One B-rep face of a CAD part: STEP entity #52863.
In plain terms, the planar face has unit normal (0, 0, 1).
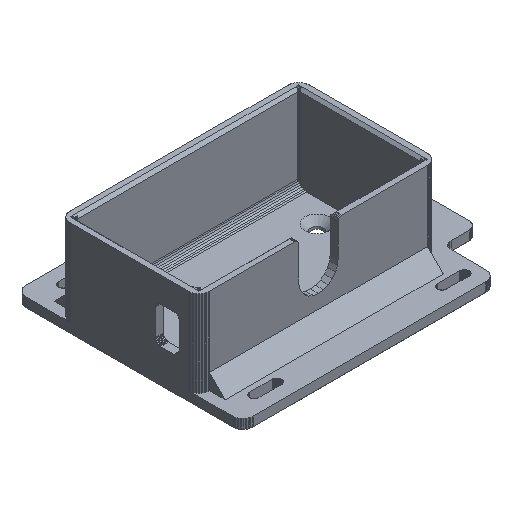
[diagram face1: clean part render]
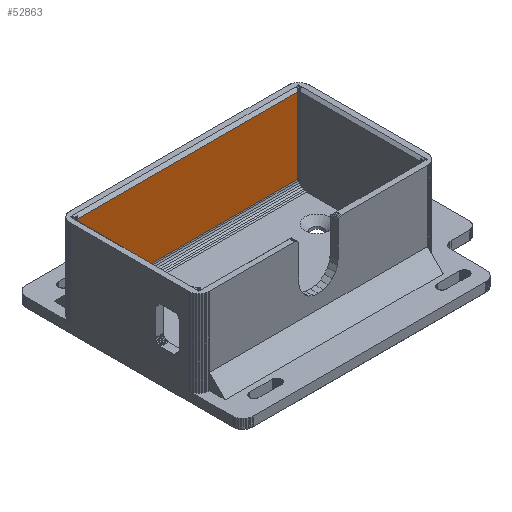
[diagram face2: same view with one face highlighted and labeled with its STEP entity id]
Its self-contained STEP definition (entity closure, numbers rounded to 3 decimals):
#43876 = PLANE('',#43877);
#43877 = AXIS2_PLACEMENT_3D('',#43878,#43879,#43880);
#43878 = CARTESIAN_POINT('',(37.5,160.35,-24.5));
#43879 = DIRECTION('',(0.,0.707,0.707)
  );
#43880 = DIRECTION('',(0.,-0.707,0.707
    ));
#49672 = VERTEX_POINT('',#49673);
#49673 = CARTESIAN_POINT('',(-47.9,159.35,-23.5));
#49699 = EDGE_CURVE('',#49700,#49672,#49702,.T.);
#49700 = VERTEX_POINT('',#49701);
#49701 = CARTESIAN_POINT('',(35.9,159.35,-23.5));
#49702 = SURFACE_CURVE('',#49703,(#49707,#49714),.PCURVE_S1.);
#49703 = LINE('',#49704,#49705);
#49704 = CARTESIAN_POINT('',(37.5,159.35,-23.5));
#49705 = VECTOR('',#49706,1.);
#49706 = DIRECTION('',(-1.,0.,0.));
#49707 = PCURVE('',#43876,#49708);
#49708 = DEFINITIONAL_REPRESENTATION('',(#49709),#49713);
#49709 = LINE('',#49710,#49711);
#49710 = CARTESIAN_POINT('',(1.414,0.));
#49711 = VECTOR('',#49712,1.);
#49712 = DIRECTION('',(0.,-1.));
#49713 = ( GEOMETRIC_REPRESENTATION_CONTEXT(2) 
PARAMETRIC_REPRESENTATION_CONTEXT() REPRESENTATION_CONTEXT('2D SPACE',''
  ) );
#49714 = PCURVE('',#49715,#49720);
#49715 = PLANE('',#49716);
#49716 = AXIS2_PLACEMENT_3D('',#49717,#49718,#49719);
#49717 = CARTESIAN_POINT('',(-47.9,160.35,-23.5));
#49718 = DIRECTION('',(0.,0.,1.));
#49719 = DIRECTION('',(1.,0.,0.));
#49720 = DEFINITIONAL_REPRESENTATION('',(#49721),#49725);
#49721 = LINE('',#49722,#49723);
#49722 = CARTESIAN_POINT('',(85.4,-1.));
#49723 = VECTOR('',#49724,1.);
#49724 = DIRECTION('',(-1.,0.));
#49725 = ( GEOMETRIC_REPRESENTATION_CONTEXT(2) 
PARAMETRIC_REPRESENTATION_CONTEXT() REPRESENTATION_CONTEXT('2D SPACE',''
  ) );
#52826 = PLANE('',#52827);
#52827 = AXIS2_PLACEMENT_3D('',#52828,#52829,#52830);
#52828 = CARTESIAN_POINT('',(35.9,160.35,-23.5));
#52829 = DIRECTION('',(-0.052,0.,
    0.999));
#52830 = DIRECTION('',(0.999,0.,
    0.052));
#52863 = ADVANCED_FACE('',(#52864),#49715,.T.);
#52864 = FACE_BOUND('',#52865,.T.);
#52865 = EDGE_LOOP('',(#52866,#52867,#52895,#52923));
#52866 = ORIENTED_EDGE('',*,*,#49699,.T.);
#52867 = ORIENTED_EDGE('',*,*,#52868,.T.);
#52868 = EDGE_CURVE('',#49672,#52869,#52871,.T.);
#52869 = VERTEX_POINT('',#52870);
#52870 = CARTESIAN_POINT('',(-47.9,130.55,-23.5));
#52871 = SURFACE_CURVE('',#52872,(#52876,#52883),.PCURVE_S1.);
#52872 = LINE('',#52873,#52874);
#52873 = CARTESIAN_POINT('',(-47.9,160.35,-23.5));
#52874 = VECTOR('',#52875,1.);
#52875 = DIRECTION('',(0.,-1.,0.));
#52876 = PCURVE('',#49715,#52877);
#52877 = DEFINITIONAL_REPRESENTATION('',(#52878),#52882);
#52878 = LINE('',#52879,#52880);
#52879 = CARTESIAN_POINT('',(0.,0.));
#52880 = VECTOR('',#52881,1.);
#52881 = DIRECTION('',(0.,-1.));
#52882 = ( GEOMETRIC_REPRESENTATION_CONTEXT(2) 
PARAMETRIC_REPRESENTATION_CONTEXT() REPRESENTATION_CONTEXT('2D SPACE',''
  ) );
#52883 = PCURVE('',#52884,#52889);
#52884 = PLANE('',#52885);
#52885 = AXIS2_PLACEMENT_3D('',#52886,#52887,#52888);
#52886 = CARTESIAN_POINT('',(-47.963,160.35,-23.497));
#52887 = DIRECTION('',(0.052,0.,
    0.999));
#52888 = DIRECTION('',(0.999,0.,
    -0.052));
#52889 = DEFINITIONAL_REPRESENTATION('',(#52890),#52894);
#52890 = LINE('',#52891,#52892);
#52891 = CARTESIAN_POINT('',(0.063,0.));
#52892 = VECTOR('',#52893,1.);
#52893 = DIRECTION('',(0.,-1.));
#52894 = ( GEOMETRIC_REPRESENTATION_CONTEXT(2) 
PARAMETRIC_REPRESENTATION_CONTEXT() REPRESENTATION_CONTEXT('2D SPACE',''
  ) );
#52895 = ORIENTED_EDGE('',*,*,#52896,.F.);
#52896 = EDGE_CURVE('',#52897,#52869,#52899,.T.);
#52897 = VERTEX_POINT('',#52898);
#52898 = CARTESIAN_POINT('',(35.9,130.55,-23.5));
#52899 = SURFACE_CURVE('',#52900,(#52904,#52911),.PCURVE_S1.);
#52900 = LINE('',#52901,#52902);
#52901 = CARTESIAN_POINT('',(37.5,130.55,-23.5));
#52902 = VECTOR('',#52903,1.);
#52903 = DIRECTION('',(-1.,0.,0.));
#52904 = PCURVE('',#49715,#52905);
#52905 = DEFINITIONAL_REPRESENTATION('',(#52906),#52910);
#52906 = LINE('',#52907,#52908);
#52907 = CARTESIAN_POINT('',(85.4,-29.8));
#52908 = VECTOR('',#52909,1.);
#52909 = DIRECTION('',(-1.,0.));
#52910 = ( GEOMETRIC_REPRESENTATION_CONTEXT(2) 
PARAMETRIC_REPRESENTATION_CONTEXT() REPRESENTATION_CONTEXT('2D SPACE',''
  ) );
#52911 = PCURVE('',#52912,#52917);
#52912 = PLANE('',#52913);
#52913 = AXIS2_PLACEMENT_3D('',#52914,#52915,#52916);
#52914 = CARTESIAN_POINT('',(37.5,129.882,-23.425));
#52915 = DIRECTION('',(0.,-0.112,
    -0.994));
#52916 = DIRECTION('',(0.,0.994,
    -0.112));
#52917 = DEFINITIONAL_REPRESENTATION('',(#52918),#52922);
#52918 = LINE('',#52919,#52920);
#52919 = CARTESIAN_POINT('',(0.672,0.));
#52920 = VECTOR('',#52921,1.);
#52921 = DIRECTION('',(0.,-1.));
#52922 = ( GEOMETRIC_REPRESENTATION_CONTEXT(2) 
PARAMETRIC_REPRESENTATION_CONTEXT() REPRESENTATION_CONTEXT('2D SPACE',''
  ) );
#52923 = ORIENTED_EDGE('',*,*,#52924,.F.);
#52924 = EDGE_CURVE('',#49700,#52897,#52925,.T.);
#52925 = SURFACE_CURVE('',#52926,(#52930,#52937),.PCURVE_S1.);
#52926 = LINE('',#52927,#52928);
#52927 = CARTESIAN_POINT('',(35.9,160.35,-23.5));
#52928 = VECTOR('',#52929,1.);
#52929 = DIRECTION('',(0.,-1.,0.));
#52930 = PCURVE('',#49715,#52931);
#52931 = DEFINITIONAL_REPRESENTATION('',(#52932),#52936);
#52932 = LINE('',#52933,#52934);
#52933 = CARTESIAN_POINT('',(83.8,0.));
#52934 = VECTOR('',#52935,1.);
#52935 = DIRECTION('',(0.,-1.));
#52936 = ( GEOMETRIC_REPRESENTATION_CONTEXT(2) 
PARAMETRIC_REPRESENTATION_CONTEXT() REPRESENTATION_CONTEXT('2D SPACE',''
  ) );
#52937 = PCURVE('',#52826,#52938);
#52938 = DEFINITIONAL_REPRESENTATION('',(#52939),#52943);
#52939 = LINE('',#52940,#52941);
#52940 = CARTESIAN_POINT('',(0.,0.));
#52941 = VECTOR('',#52942,1.);
#52942 = DIRECTION('',(0.,-1.));
#52943 = ( GEOMETRIC_REPRESENTATION_CONTEXT(2) 
PARAMETRIC_REPRESENTATION_CONTEXT() REPRESENTATION_CONTEXT('2D SPACE',''
  ) );
